VERSION 5.8 ;

BUSBITCHARS "[]" ;
DIVIDERCHAR "/" ;

UNITS
    DATABASE MICRONS 1000 ;
END UNITS

LAYER M1
    TYPE ROUTING ;
    DIRECTION HORIZONTAL ;
    PITCH 0.20 ;
    WIDTH 0.10 ;
    SPACING 0.10 ;
END M1

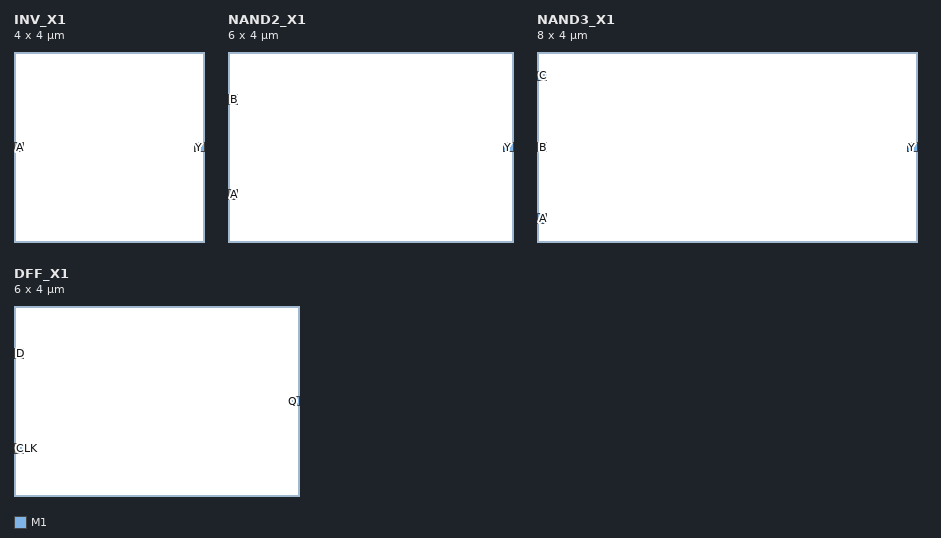
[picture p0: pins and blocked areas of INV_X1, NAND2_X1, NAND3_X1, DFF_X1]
MACRO INV_X1
    CLASS CORE ;
    ORIGIN 0 0 ;
    SIZE 4 BY 4;
    SYMMETRY X Y ;

    PIN A
        DIRECTION INPUT ;
        USE SIGNAL ;
        PORT
            LAYER M1 ;
            RECT 0.00 1.90 0.20 2.10 ;
        END
    END A

    PIN Y
        DIRECTION OUTPUT ;
        USE SIGNAL ;
        PORT
            LAYER M1 ;
            RECT 3.80 1.90 4.00 2.10 ;
        END
    END Y
END INV_X1

MACRO NAND2_X1
    CLASS CORE ;
    ORIGIN 0 0 ;
    SIZE 6 BY 4 ;
    SYMMETRY X Y ;

    PIN A
        DIRECTION INPUT ;
        USE SIGNAL ;
        PORT
            LAYER M1 ;
            RECT 0.00 0.90 0.20 1.10 ;
        END
    END A

    PIN B
        DIRECTION INPUT ;
        USE SIGNAL ;
        PORT
            LAYER M1 ;
            RECT 0.00 2.90 0.20 3.10 ;
        END
    END B

    PIN Y
        DIRECTION OUTPUT ;
        USE SIGNAL ;
        PORT
            LAYER M1 ;
            RECT 5.80 1.90 6.00 2.10 ;
        END
    END Y
END NAND2_X1

MACRO NAND3_X1
    CLASS CORE ;
    ORIGIN 0 0 ;
    SIZE 8 BY 4 ;
    SYMMETRY X Y ;

    PIN A
        DIRECTION INPUT ;
        USE SIGNAL ;
        PORT
            LAYER M1 ;
            RECT 0.00 0.40 0.20 0.60 ;
        END
    END A

    PIN B
        DIRECTION INPUT ;
        USE SIGNAL ;
        PORT
            LAYER M1 ;
            RECT 0.00 1.90 0.20 2.10 ;
        END
    END B

    PIN C
        DIRECTION INPUT ;
        USE SIGNAL ;
        PORT
            LAYER M1 ;
            RECT 0.00 3.40 0.20 3.60 ;
        END
    END C

    PIN Y
        DIRECTION OUTPUT ;
        USE SIGNAL ;
        PORT
            LAYER M1 ;
            RECT 7.80 1.90 8.00 2.10 ;
        END
    END Y
END NAND3_X1

MACRO DFF_X1
    CLASS CORE ;
    ORIGIN 0 0 ;
    SIZE 6 BY 4 ;
    SYMMETRY X Y ;

    PIN D
        DIRECTION INPUT ;
        USE SIGNAL ;
        PORT
            LAYER M1 ;
            RECT 0.00 2.90 0.20 3.10 ;
        END
    END D

    PIN CLK
        DIRECTION INPUT ;
        USE CLOCK ;
        PORT
            LAYER M1 ;
            RECT 0.00 0.90 0.20 1.10 ;
        END
    END CLK

    PIN Q
        DIRECTION OUTPUT ;
        USE SIGNAL ;
        PORT
            LAYER M1 ;
            RECT 5.80 1.90 6.00 2.10 ;
        END
    END Q
END DFF_X1

END LIBRARY

